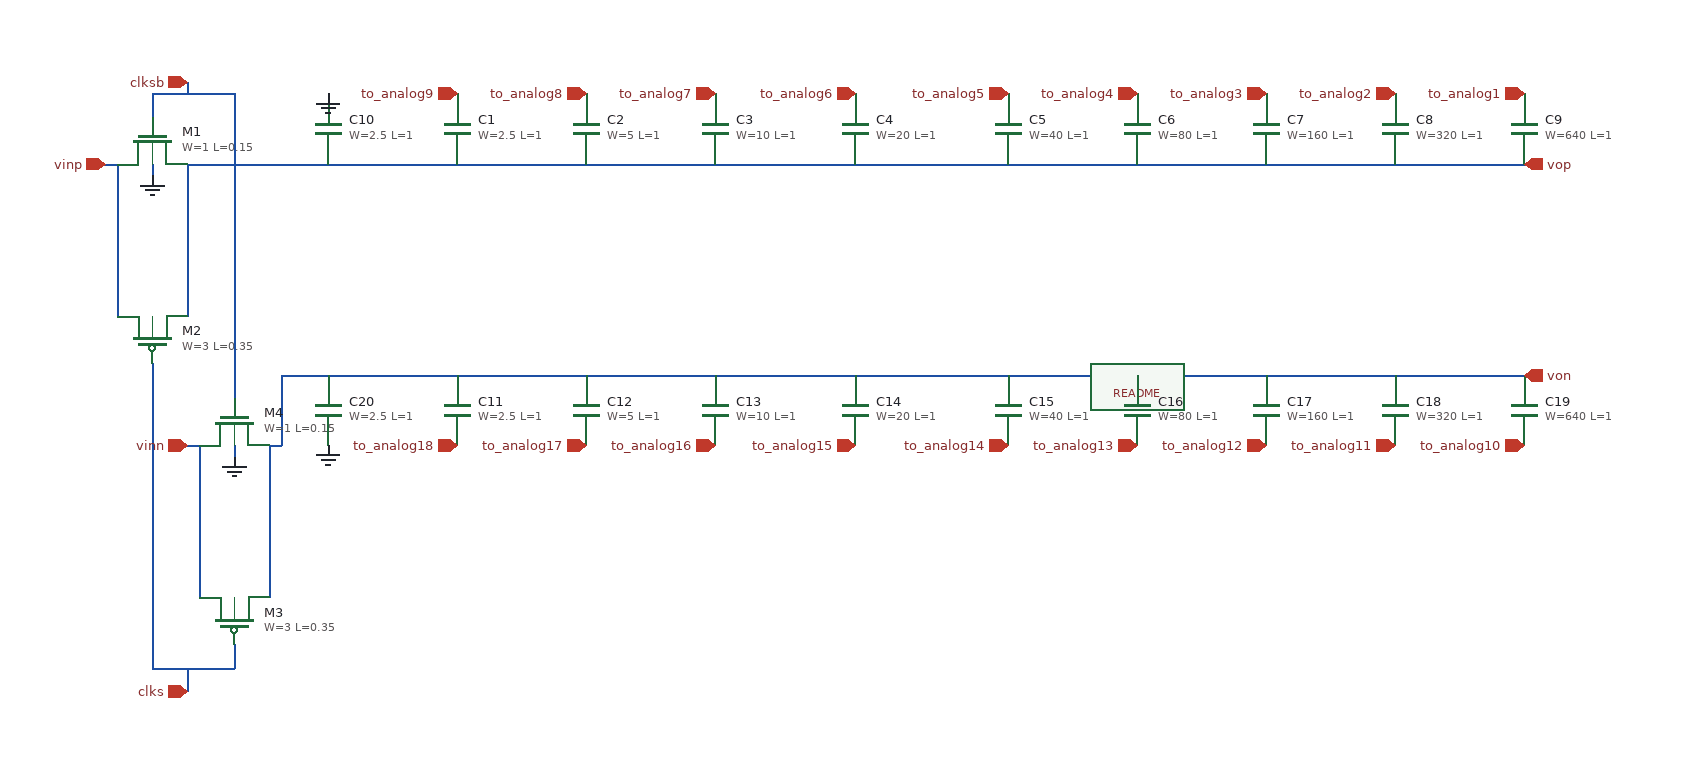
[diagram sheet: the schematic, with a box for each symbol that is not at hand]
v {xschem version=3.0.0 file_version=1.2 }
G {}
K {}
V {}
S {}
E {}
N -280 -60 -170 -60 {
lab=vop}
N -170 -60 -60 -60 {
lab=vop}
N -60 -60 50 -60 {
lab=vop}
N 50 -60 170 -60 {
lab=vop}
N 170 -60 300 -60 {
lab=vop}
N 300 -60 410 -60 {
lab=vop}
N 410 -60 520 -60 {
lab=vop}
N 520 -60 630 -60 {
lab=vop}
N 630 -60 740 -60 {
lab=vop}
N -280 120 -170 120 {
lab=von}
N -170 120 -60 120 {
lab=von}
N -60 120 50 120 {
lab=von}
N 50 120 170 120 {
lab=von}
N 170 120 300 120 {
lab=von}
N 300 120 410 120 {
lab=von}
N 410 120 520 120 {
lab=von}
N 520 120 630 120 {
lab=von}
N 630 120 740 120 {
lab=von}
N -460 -60 -460 70 { lab=vinp}
N -400 -60 -400 70 { lab=vop}
N -430 110 -430 130 { lab=clks}
N -430 -120 -430 -100 { lab=clksb}
N -470 -60 -460 -60 { lab=vinp}
N -400 -60 -280 -60 { lab=vop}
N -390 180 -390 310 { lab=vinn}
N -330 180 -330 310 { lab=von}
N -360 350 -360 370 { lab=clks}
N -360 120 -360 140 { lab=clksb}
N -400 180 -390 180 { lab=vinn}
N -330 180 -320 180 { lab=von}
N -320 120 -320 180 { lab=von}
N -320 120 -280 120 { lab=von}
N -430 -120 -360 -120 { lab=clksb}
N -360 -120 -360 120 { lab=clksb}
N -430 370 -360 370 { lab=clks}
N -430 130 -430 370 { lab=clks}
N -400 -130 -400 -120 { lab=clksb}
N -400 370 -400 390 { lab=clks}
N -430 -60 -430 -50 { lab=GND}
N -360 180 -360 190 { lab=GND}
C {xschem_sky130/sky130_fd_pr/README.md} 410 130 0 0 {}
C {xschem_sky130/sky130_fd_pr/cap_mim_m3_1.sym} -170 -90 0 0 {name=C1 model=cap_mim_m3_1 W=2.5 L=1 MF=1 spiceprefix=X}
C {xschem_sky130/sky130_fd_pr/cap_mim_m3_1.sym} -60 -90 0 0 {name=C2 model=cap_mim_m3_1 W=5 L=1 MF=1 spiceprefix=X}
C {xschem_sky130/sky130_fd_pr/cap_mim_m3_1.sym} 50 -90 0 0 {name=C3 model=cap_mim_m3_1 W=10 L=1 MF=1 spiceprefix=X}
C {xschem_sky130/sky130_fd_pr/cap_mim_m3_1.sym} 170 -90 0 0 {name=C4 model=cap_mim_m3_1 W=20 L=1 MF=1 spiceprefix=X}
C {xschem_sky130/sky130_fd_pr/cap_mim_m3_1.sym} 300 -90 0 0 {name=C5 model=cap_mim_m3_1 W=40 L=1 MF=1 spiceprefix=X}
C {xschem_sky130/sky130_fd_pr/cap_mim_m3_1.sym} 410 -90 0 0 {name=C6 model=cap_mim_m3_1 W=80 L=1 MF=1 spiceprefix=X}
C {xschem_sky130/sky130_fd_pr/cap_mim_m3_1.sym} 520 -90 0 0 {name=C7 model=cap_mim_m3_1 W=160 L=1 MF=1 spiceprefix=X}
C {xschem_sky130/sky130_fd_pr/cap_mim_m3_1.sym} 630 -90 0 0 {name=C8 model=cap_mim_m3_1 W=320 L=1 MF=1 spiceprefix=X}
C {xschem_sky130/sky130_fd_pr/cap_mim_m3_1.sym} 740 -90 0 0 {name=C9 model=cap_mim_m3_1 W=640 L=1 MF=1 spiceprefix=X}
C {xschem_sky130/sky130_fd_pr/cap_mim_m3_1.sym} -280 -90 0 0 {name=C10 model=cap_mim_m3_1 W=2.5 L=1 MF=1 spiceprefix=X}
C {xschem_sky130/sky130_fd_pr/cap_mim_m3_1.sym} -170 150 0 0 {name=C11 model=cap_mim_m3_1 W=2.5 L=1 MF=1 spiceprefix=X}
C {xschem_sky130/sky130_fd_pr/cap_mim_m3_1.sym} -60 150 0 0 {name=C12 model=cap_mim_m3_1 W=5 L=1 MF=1 spiceprefix=X}
C {xschem_sky130/sky130_fd_pr/cap_mim_m3_1.sym} 50 150 0 0 {name=C13 model=cap_mim_m3_1 W=10 L=1 MF=1 spiceprefix=X}
C {xschem_sky130/sky130_fd_pr/cap_mim_m3_1.sym} 170 150 0 0 {name=C14 model=cap_mim_m3_1 W=20 L=1 MF=1 spiceprefix=X}
C {xschem_sky130/sky130_fd_pr/cap_mim_m3_1.sym} 300 150 0 0 {name=C15 model=cap_mim_m3_1 W=40 L=1 MF=1 spiceprefix=X}
C {xschem_sky130/sky130_fd_pr/cap_mim_m3_1.sym} 410 150 0 0 {name=C16 model=cap_mim_m3_1 W=80 L=1 MF=1 spiceprefix=X}
C {xschem_sky130/sky130_fd_pr/cap_mim_m3_1.sym} 520 150 0 0 {name=C17 model=cap_mim_m3_1 W=160 L=1 MF=1 spiceprefix=X}
C {xschem_sky130/sky130_fd_pr/cap_mim_m3_1.sym} 630 150 0 0 {name=C18 model=cap_mim_m3_1 W=320 L=1 MF=1 spiceprefix=X}
C {xschem_sky130/sky130_fd_pr/cap_mim_m3_1.sym} 740 150 0 0 {name=C19 model=cap_mim_m3_1 W=640 L=1 MF=1 spiceprefix=X}
C {xschem_sky130/sky130_fd_pr/cap_mim_m3_1.sym} -280 150 0 0 {name=C20 model=cap_mim_m3_1 W=2.5 L=1 MF=1 spiceprefix=X}
C {ipin.sym} -170 -120 0 0 {name=p2 lab=to_analog9}
C {ipin.sym} -60 -120 0 0 {name=p3 lab=to_analog8}
C {ipin.sym} 50 -120 0 0 {name=p4 lab=to_analog7}
C {ipin.sym} 170 -120 0 0 {name=p5 lab=to_analog6}
C {ipin.sym} 300 -120 0 0 {name=p6 lab=to_analog5}
C {ipin.sym} 410 -120 0 0 {name=p8 lab=to_analog4}
C {ipin.sym} 520 -120 0 0 {name=p9 lab=to_analog3}
C {ipin.sym} 630 -120 0 0 {name=p10 lab=to_analog2}
C {ipin.sym} 740 -120 0 0 {name=p11 lab=to_analog1}
C {ipin.sym} -170 180 0 0 {name=p13 lab=to_analog18}
C {ipin.sym} -60 180 0 0 {name=p14 lab=to_analog17}
C {ipin.sym} 50 180 0 0 {name=p15 lab=to_analog16}
C {ipin.sym} 170 180 0 0 {name=p16 lab=to_analog15}
C {ipin.sym} 300 180 0 0 {name=p17 lab=to_analog14}
C {ipin.sym} 410 180 0 0 {name=p18 lab=to_analog13}
C {ipin.sym} 520 180 0 0 {name=p19 lab=to_analog12}
C {ipin.sym} 630 180 0 0 {name=p20 lab=to_analog11}
C {ipin.sym} 740 180 0 0 {name=p21 lab=to_analog10}
C {opin.sym} 740 -60 0 0 {name=p24 lab=vop}
C {opin.sym} 740 120 0 0 {name=p25 lab=von}
C {ipin.sym} -400 180 0 0 {name=p26 lab=vinn}
C {gnd.sym} -280 180 0 0 {name=l1 lab=GND}
C {gnd.sym} -280 -120 2 0 {name=l2 lab=GND}
C {xschem_sky130/sky130_fd_pr/pfet3_01v8_lvt.sym} -430 90 3 0 {name=M2
L=0.35
W=3
body=VDD
nf=1
mult=1
ad="'int((nf+1)/2) * W/nf * 0.29'" 
pd="'2*int((nf+1)/2) * (W/nf + 0.29)'"
as="'int((nf+2)/2) * W/nf * 0.29'" 
ps="'2*int((nf+2)/2) * (W/nf + 0.29)'"
nrd="'0.29 / W'" nrs="'0.29 / W'"
sa=0 sb=0 sd=0
model=pfet_01v8_lvt
spiceprefix=X
}
C {xschem_sky130/sky130_fd_pr/nfet_01v8_lvt.sym} -430 -80 3 1 {name=M1
L=0.15
W=1
nf=1
mult=1
ad="'int((nf+1)/2) * W/nf * 0.29'" 
pd="'2*int((nf+1)/2) * (W/nf + 0.29)'"
as="'int((nf+2)/2) * W/nf * 0.29'" 
ps="'2*int((nf+2)/2) * (W/nf + 0.29)'"
nrd="'0.29 / W'" nrs="'0.29 / W'"
sa=0 sb=0 sd=0
model=nfet_01v8_lvt
spiceprefix=X
}
C {xschem_sky130/sky130_fd_pr/pfet3_01v8_lvt.sym} -360 330 3 0 {name=M3
L=0.35
W=3
body=VDD
nf=1
mult=1
ad="'int((nf+1)/2) * W/nf * 0.29'" 
pd="'2*int((nf+1)/2) * (W/nf + 0.29)'"
as="'int((nf+2)/2) * W/nf * 0.29'" 
ps="'2*int((nf+2)/2) * (W/nf + 0.29)'"
nrd="'0.29 / W'" nrs="'0.29 / W'"
sa=0 sb=0 sd=0
model=pfet_01v8_lvt
spiceprefix=X
}
C {xschem_sky130/sky130_fd_pr/nfet_01v8_lvt.sym} -360 160 3 1 {name=M4
L=0.15
W=1
nf=1
mult=1
ad="'int((nf+1)/2) * W/nf * 0.29'" 
pd="'2*int((nf+1)/2) * (W/nf + 0.29)'"
as="'int((nf+2)/2) * W/nf * 0.29'" 
ps="'2*int((nf+2)/2) * (W/nf + 0.29)'"
nrd="'0.29 / W'" nrs="'0.29 / W'"
sa=0 sb=0 sd=0
model=nfet_01v8_lvt
spiceprefix=X
}
C {ipin.sym} -470 -60 0 0 {name=p1 lab=vinp}
C {ipin.sym} -400 -130 1 0 {name=p12 lab=clksb}
C {ipin.sym} -400 390 3 0 {name=p22 lab=clks}
C {gnd.sym} -360 190 0 0 {name=l3 lab=GND}
C {gnd.sym} -430 -50 0 0 {name=l4 lab=GND}
